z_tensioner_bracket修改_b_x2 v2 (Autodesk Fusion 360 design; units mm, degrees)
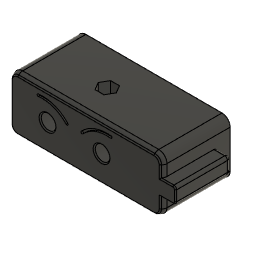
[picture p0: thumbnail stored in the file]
named bodies: "z_tensioner_bracket_b_x2"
